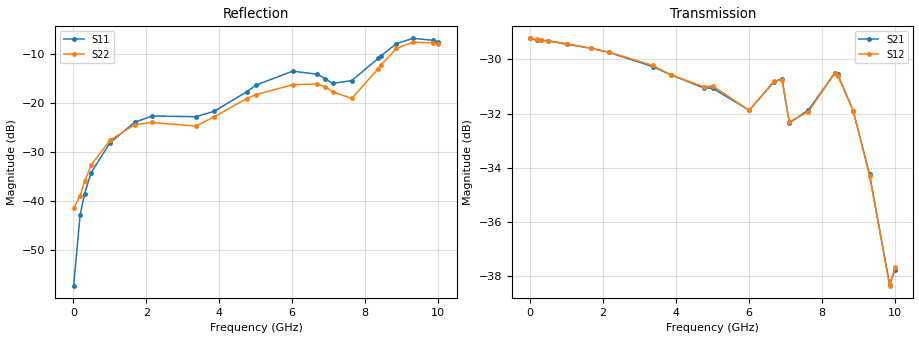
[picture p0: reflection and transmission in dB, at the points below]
! Device ID: PE43705
! Serial: 1
! Insertion: A
! Impedance: 50 ohm
! Temp: 25C
! VDD: 3.400V
! Attenuation Step: 28.25dB
#  Hz  S  RI  R  50
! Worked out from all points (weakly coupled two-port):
!   401 points, 10 MHz to 10.01 GHz, reference 50 ohm
!   highest |S21| = -29.23 dB at 10 MHz (marker M1); lowest = -38.3 dB at 9.86 GHz (marker M2)
!   lowest |S11| = -57.4 dB at 10 MHz (marker M3), VSWR 1.00, Z = 49.9 + j0.0397 ohm
!   |S11| at or under -10 dB: start of sweep to 8.493 GHz
!   |S22| runs from -41.6 to -7.5 dB; largest |S21 - S12| = 0.00071
!   S11 on the Smith chart (normalised r, x): 10 MHz: 1.00, +0.00; 4.76 GHz: 0.80, +0.12; 8.435 GHz: 0.80, +0.53; 9.31 GHz: 0.52, +0.55; 10.01 GHz: 0.47, +0.33
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1e7  -0.0013 0.000398  0.0346 -0.000145  0.0346 -0.000144  -0.00835 0.000469
1.85e8  -0.0018 0.00686  0.0343 -0.00167  0.0344 -0.00164  -0.00815 0.00775
3.1e8  -0.0037 0.0112  0.0342 -0.00267  0.0342 -0.0027  -0.00974 0.0124
4.85e8  -0.0084 0.0173  0.034 -0.00411  0.034 -0.00412  -0.0136 0.0186
1.01e9  -0.032 0.0226  0.0327 -0.00833  0.0328 -0.0083  -0.0329 0.0253
1.685e9  -0.0624 0.0102  0.0305 -0.013  0.0305 -0.013  -0.057 0.0178
2.16e9  -0.0731 -0.00429  0.0284 -0.016  0.0284 -0.0161  -0.0624 0.00768
3.36e9  -0.0719 -0.0032  0.0217 -0.0217  0.0218 -0.0218  -0.0564 0.0121
3.86e9  -0.0787 0.0217  0.0188 -0.0229  0.0188 -0.0229  -0.0666 0.0269
4.76e9  -0.1058 0.0749  0.0143 -0.0241  0.0144 -0.0242  -0.0937 0.0583
5.01e9  -0.1214 0.0902  0.0135 -0.0245  0.0137 -0.0247  -0.1026 0.0642
6.01e9  -0.1759 0.1141  0.00824 -0.0241  0.00823 -0.0241  -0.1302 0.0791
6.685e9  -0.1666 0.102  0.00639 -0.028  0.00635 -0.0281  -0.1371 0.0728
6.91e9  -0.1471 0.0967  0.00273 -0.029  0.00261 -0.0289  -0.1256 0.0725
7.11e9  -0.1314 0.0864  0.000967 -0.0241  0.00133 -0.0242  -0.1049 0.0751
7.635e9  -0.0825 0.1466  0.00237 -0.0254  0.00241 -0.0252  -0.0558 0.0954
8.36e9  -0.0222 0.2822  -0.00672 -0.0291  -0.00662 -0.0291  -0.0364 0.2197
8.435e9  -0.0245 0.2998  -0.00826 -0.0285  -0.00809 -0.0284  -0.0397 0.2389
8.86e9  -0.0749 0.3934  -0.0131 -0.0218  -0.0129 -0.0219  -0.0974 0.3445
9.31e9  -0.1615 0.4235  -0.0124 -0.0149  -0.0122 -0.0149  -0.1895 0.368
9.86e9  -0.2764 0.334  -0.00437 -0.0113  -0.00447 -0.0112  -0.3169 0.257
1.001e10  -0.2991 0.2893  -0.00174 -0.0128  -0.00195 -0.0129  -0.3469 0.1979
